VERSION 5.8 ;
BUSBITCHARS "[]" ;
DIVIDERCHAR "/" ;
UNITS
    DATABASE MICRONS 1000 ;
END UNITS

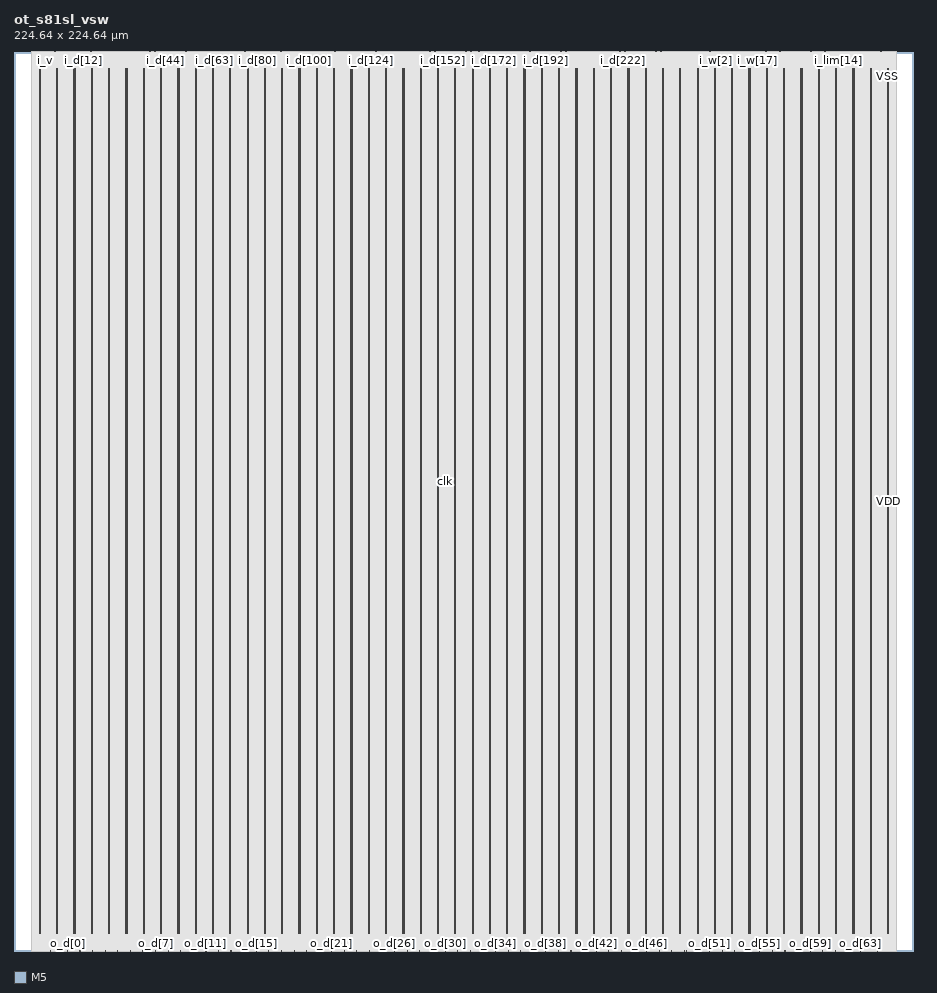
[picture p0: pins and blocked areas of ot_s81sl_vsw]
MACRO ot_s81sl_vsw
  FOREIGN ot_s81sl_vsw 0 0 ;
  CLASS BLOCK ;
  SIZE 224.64 BY 224.64 ;
  PIN clk
    DIRECTION INPUT ;
    USE SIGNAL ;
    PORT
      LAYER M5 ;
        RECT  107.46 116.94 107.508 117.42 ;
    END
  END clk
  PIN i_d[0]
    DIRECTION INPUT ;
    USE SIGNAL ;
    PORT
      LAYER M5 ;
        RECT  9.552 224.556 9.576 224.64 ;
    END
  END i_d[0]
  PIN i_d[100]
    DIRECTION INPUT ;
    USE SIGNAL ;
    PORT
      LAYER M5 ;
        RECT  73.68 224.556 73.704 224.64 ;
    END
  END i_d[100]
  PIN i_d[101]
    DIRECTION INPUT ;
    USE SIGNAL ;
    PORT
      LAYER M5 ;
        RECT  74.304 224.556 74.328 224.64 ;
    END
  END i_d[101]
  PIN i_d[102]
    DIRECTION INPUT ;
    USE SIGNAL ;
    PORT
      LAYER M5 ;
        RECT  74.928 224.556 74.952 224.64 ;
    END
  END i_d[102]
  PIN i_d[103]
    DIRECTION INPUT ;
    USE SIGNAL ;
    PORT
      LAYER M5 ;
        RECT  75.6 224.556 75.624 224.64 ;
    END
  END i_d[103]
  PIN i_d[104]
    DIRECTION INPUT ;
    USE SIGNAL ;
    PORT
      LAYER M5 ;
        RECT  76.224 224.556 76.248 224.64 ;
    END
  END i_d[104]
  PIN i_d[105]
    DIRECTION INPUT ;
    USE SIGNAL ;
    PORT
      LAYER M5 ;
        RECT  76.896 224.556 76.92 224.64 ;
    END
  END i_d[105]
  PIN i_d[106]
    DIRECTION INPUT ;
    USE SIGNAL ;
    PORT
      LAYER M5 ;
        RECT  77.52 224.556 77.544 224.64 ;
    END
  END i_d[106]
  PIN i_d[107]
    DIRECTION INPUT ;
    USE SIGNAL ;
    PORT
      LAYER M5 ;
        RECT  78.144 224.556 78.168 224.64 ;
    END
  END i_d[107]
  PIN i_d[108]
    DIRECTION INPUT ;
    USE SIGNAL ;
    PORT
      LAYER M5 ;
        RECT  78.816 224.556 78.84 224.64 ;
    END
  END i_d[108]
  PIN i_d[109]
    DIRECTION INPUT ;
    USE SIGNAL ;
    PORT
      LAYER M5 ;
        RECT  79.44 224.556 79.464 224.64 ;
    END
  END i_d[109]
  PIN i_d[10]
    DIRECTION INPUT ;
    USE SIGNAL ;
    PORT
      LAYER M5 ;
        RECT  15.984 224.556 16.008 224.64 ;
    END
  END i_d[10]
  PIN i_d[110]
    DIRECTION INPUT ;
    USE SIGNAL ;
    PORT
      LAYER M5 ;
        RECT  80.112 224.556 80.136 224.64 ;
    END
  END i_d[110]
  PIN i_d[111]
    DIRECTION INPUT ;
    USE SIGNAL ;
    PORT
      LAYER M5 ;
        RECT  80.736 224.556 80.76 224.64 ;
    END
  END i_d[111]
  PIN i_d[112]
    DIRECTION INPUT ;
    USE SIGNAL ;
    PORT
      LAYER M5 ;
        RECT  81.408 224.556 81.432 224.64 ;
    END
  END i_d[112]
  PIN i_d[113]
    DIRECTION INPUT ;
    USE SIGNAL ;
    PORT
      LAYER M5 ;
        RECT  82.032 224.556 82.056 224.64 ;
    END
  END i_d[113]
  PIN i_d[114]
    DIRECTION INPUT ;
    USE SIGNAL ;
    PORT
      LAYER M5 ;
        RECT  82.656 224.556 82.68 224.64 ;
    END
  END i_d[114]
  PIN i_d[115]
    DIRECTION INPUT ;
    USE SIGNAL ;
    PORT
      LAYER M5 ;
        RECT  83.28 224.556 83.304 224.64 ;
    END
  END i_d[115]
  PIN i_d[116]
    DIRECTION INPUT ;
    USE SIGNAL ;
    PORT
      LAYER M5 ;
        RECT  83.952 224.556 83.976 224.64 ;
    END
  END i_d[116]
  PIN i_d[117]
    DIRECTION INPUT ;
    USE SIGNAL ;
    PORT
      LAYER M5 ;
        RECT  84.576 224.556 84.6 224.64 ;
    END
  END i_d[117]
  PIN i_d[118]
    DIRECTION INPUT ;
    USE SIGNAL ;
    PORT
      LAYER M5 ;
        RECT  85.2 224.556 85.224 224.64 ;
    END
  END i_d[118]
  PIN i_d[119]
    DIRECTION INPUT ;
    USE SIGNAL ;
    PORT
      LAYER M5 ;
        RECT  85.872 224.556 85.896 224.64 ;
    END
  END i_d[119]
  PIN i_d[11]
    DIRECTION INPUT ;
    USE SIGNAL ;
    PORT
      LAYER M5 ;
        RECT  16.656 224.556 16.68 224.64 ;
    END
  END i_d[11]
  PIN i_d[120]
    DIRECTION INPUT ;
    USE SIGNAL ;
    PORT
      LAYER M5 ;
        RECT  86.496 224.556 86.52 224.64 ;
    END
  END i_d[120]
  PIN i_d[121]
    DIRECTION INPUT ;
    USE SIGNAL ;
    PORT
      LAYER M5 ;
        RECT  87.12 224.556 87.144 224.64 ;
    END
  END i_d[121]
  PIN i_d[122]
    DIRECTION INPUT ;
    USE SIGNAL ;
    PORT
      LAYER M5 ;
        RECT  87.744 224.556 87.768 224.64 ;
    END
  END i_d[122]
  PIN i_d[123]
    DIRECTION INPUT ;
    USE SIGNAL ;
    PORT
      LAYER M5 ;
        RECT  88.416 224.556 88.44 224.64 ;
    END
  END i_d[123]
  PIN i_d[124]
    DIRECTION INPUT ;
    USE SIGNAL ;
    PORT
      LAYER M5 ;
        RECT  89.04 224.556 89.064 224.64 ;
    END
  END i_d[124]
  PIN i_d[125]
    DIRECTION INPUT ;
    USE SIGNAL ;
    PORT
      LAYER M5 ;
        RECT  89.712 224.556 89.736 224.64 ;
    END
  END i_d[125]
  PIN i_d[126]
    DIRECTION INPUT ;
    USE SIGNAL ;
    PORT
      LAYER M5 ;
        RECT  90.336 224.556 90.36 224.64 ;
    END
  END i_d[126]
  PIN i_d[127]
    DIRECTION INPUT ;
    USE SIGNAL ;
    PORT
      LAYER M5 ;
        RECT  91.008 224.556 91.032 224.64 ;
    END
  END i_d[127]
  PIN i_d[128]
    DIRECTION INPUT ;
    USE SIGNAL ;
    PORT
      LAYER M5 ;
        RECT  91.632 224.556 91.656 224.64 ;
    END
  END i_d[128]
  PIN i_d[129]
    DIRECTION INPUT ;
    USE SIGNAL ;
    PORT
      LAYER M5 ;
        RECT  92.256 224.556 92.28 224.64 ;
    END
  END i_d[129]
  PIN i_d[12]
    DIRECTION INPUT ;
    USE SIGNAL ;
    PORT
      LAYER M5 ;
        RECT  17.28 224.556 17.304 224.64 ;
    END
  END i_d[12]
  PIN i_d[130]
    DIRECTION INPUT ;
    USE SIGNAL ;
    PORT
      LAYER M5 ;
        RECT  92.928 224.556 92.952 224.64 ;
    END
  END i_d[130]
  PIN i_d[131]
    DIRECTION INPUT ;
    USE SIGNAL ;
    PORT
      LAYER M5 ;
        RECT  93.552 224.556 93.576 224.64 ;
    END
  END i_d[131]
  PIN i_d[132]
    DIRECTION INPUT ;
    USE SIGNAL ;
    PORT
      LAYER M5 ;
        RECT  94.176 224.556 94.2 224.64 ;
    END
  END i_d[132]
  PIN i_d[133]
    DIRECTION INPUT ;
    USE SIGNAL ;
    PORT
      LAYER M5 ;
        RECT  94.848 224.556 94.872 224.64 ;
    END
  END i_d[133]
  PIN i_d[134]
    DIRECTION INPUT ;
    USE SIGNAL ;
    PORT
      LAYER M5 ;
        RECT  95.472 224.556 95.496 224.64 ;
    END
  END i_d[134]
  PIN i_d[135]
    DIRECTION INPUT ;
    USE SIGNAL ;
    PORT
      LAYER M5 ;
        RECT  96.096 224.556 96.12 224.64 ;
    END
  END i_d[135]
  PIN i_d[136]
    DIRECTION INPUT ;
    USE SIGNAL ;
    PORT
      LAYER M5 ;
        RECT  96.768 224.556 96.792 224.64 ;
    END
  END i_d[136]
  PIN i_d[137]
    DIRECTION INPUT ;
    USE SIGNAL ;
    PORT
      LAYER M5 ;
        RECT  97.392 224.556 97.416 224.64 ;
    END
  END i_d[137]
  PIN i_d[138]
    DIRECTION INPUT ;
    USE SIGNAL ;
    PORT
      LAYER M5 ;
        RECT  98.016 224.556 98.04 224.64 ;
    END
  END i_d[138]
  PIN i_d[139]
    DIRECTION INPUT ;
    USE SIGNAL ;
    PORT
      LAYER M5 ;
        RECT  98.688 224.556 98.712 224.64 ;
    END
  END i_d[139]
  PIN i_d[13]
    DIRECTION INPUT ;
    USE SIGNAL ;
    PORT
      LAYER M5 ;
        RECT  17.904 224.556 17.928 224.64 ;
    END
  END i_d[13]
  PIN i_d[140]
    DIRECTION INPUT ;
    USE SIGNAL ;
    PORT
      LAYER M5 ;
        RECT  99.312 224.556 99.336 224.64 ;
    END
  END i_d[140]
  PIN i_d[141]
    DIRECTION INPUT ;
    USE SIGNAL ;
    PORT
      LAYER M5 ;
        RECT  99.936 224.556 99.96 224.64 ;
    END
  END i_d[141]
  PIN i_d[142]
    DIRECTION INPUT ;
    USE SIGNAL ;
    PORT
      LAYER M5 ;
        RECT  100.56 224.556 100.584 224.64 ;
    END
  END i_d[142]
  PIN i_d[143]
    DIRECTION INPUT ;
    USE SIGNAL ;
    PORT
      LAYER M5 ;
        RECT  101.232 224.556 101.256 224.64 ;
    END
  END i_d[143]
  PIN i_d[144]
    DIRECTION INPUT ;
    USE SIGNAL ;
    PORT
      LAYER M5 ;
        RECT  101.856 224.556 101.88 224.64 ;
    END
  END i_d[144]
  PIN i_d[145]
    DIRECTION INPUT ;
    USE SIGNAL ;
    PORT
      LAYER M5 ;
        RECT  102.528 224.556 102.552 224.64 ;
    END
  END i_d[145]
  PIN i_d[146]
    DIRECTION INPUT ;
    USE SIGNAL ;
    PORT
      LAYER M5 ;
        RECT  103.152 224.556 103.176 224.64 ;
    END
  END i_d[146]
  PIN i_d[147]
    DIRECTION INPUT ;
    USE SIGNAL ;
    PORT
      LAYER M5 ;
        RECT  103.824 224.556 103.848 224.64 ;
    END
  END i_d[147]
  PIN i_d[148]
    DIRECTION INPUT ;
    USE SIGNAL ;
    PORT
      LAYER M5 ;
        RECT  104.448 224.556 104.472 224.64 ;
    END
  END i_d[148]
  PIN i_d[149]
    DIRECTION INPUT ;
    USE SIGNAL ;
    PORT
      LAYER M5 ;
        RECT  105.072 224.556 105.096 224.64 ;
    END
  END i_d[149]
  PIN i_d[14]
    DIRECTION INPUT ;
    USE SIGNAL ;
    PORT
      LAYER M5 ;
        RECT  18.576 224.556 18.6 224.64 ;
    END
  END i_d[14]
  PIN i_d[150]
    DIRECTION INPUT ;
    USE SIGNAL ;
    PORT
      LAYER M5 ;
        RECT  105.744 224.556 105.768 224.64 ;
    END
  END i_d[150]
  PIN i_d[151]
    DIRECTION INPUT ;
    USE SIGNAL ;
    PORT
      LAYER M5 ;
        RECT  106.368 224.556 106.392 224.64 ;
    END
  END i_d[151]
  PIN i_d[152]
    DIRECTION INPUT ;
    USE SIGNAL ;
    PORT
      LAYER M5 ;
        RECT  107.04 224.556 107.064 224.64 ;
    END
  END i_d[152]
  PIN i_d[153]
    DIRECTION INPUT ;
    USE SIGNAL ;
    PORT
      LAYER M5 ;
        RECT  107.664 224.556 107.688 224.64 ;
    END
  END i_d[153]
  PIN i_d[154]
    DIRECTION INPUT ;
    USE SIGNAL ;
    PORT
      LAYER M5 ;
        RECT  108.288 224.556 108.312 224.64 ;
    END
  END i_d[154]
  PIN i_d[155]
    DIRECTION INPUT ;
    USE SIGNAL ;
    PORT
      LAYER M5 ;
        RECT  108.912 224.556 108.936 224.64 ;
    END
  END i_d[155]
  PIN i_d[156]
    DIRECTION INPUT ;
    USE SIGNAL ;
    PORT
      LAYER M5 ;
        RECT  109.584 224.556 109.608 224.64 ;
    END
  END i_d[156]
  PIN i_d[157]
    DIRECTION INPUT ;
    USE SIGNAL ;
    PORT
      LAYER M5 ;
        RECT  110.208 224.556 110.232 224.64 ;
    END
  END i_d[157]
  PIN i_d[158]
    DIRECTION INPUT ;
    USE SIGNAL ;
    PORT
      LAYER M5 ;
        RECT  110.832 224.556 110.856 224.64 ;
    END
  END i_d[158]
  PIN i_d[159]
    DIRECTION INPUT ;
    USE SIGNAL ;
    PORT
      LAYER M5 ;
        RECT  111.504 224.556 111.528 224.64 ;
    END
  END i_d[159]
  PIN i_d[15]
    DIRECTION INPUT ;
    USE SIGNAL ;
    PORT
      LAYER M5 ;
        RECT  19.2 224.556 19.224 224.64 ;
    END
  END i_d[15]
  PIN i_d[160]
    DIRECTION INPUT ;
    USE SIGNAL ;
    PORT
      LAYER M5 ;
        RECT  112.128 224.556 112.152 224.64 ;
    END
  END i_d[160]
  PIN i_d[161]
    DIRECTION INPUT ;
    USE SIGNAL ;
    PORT
      LAYER M5 ;
        RECT  112.8 224.556 112.824 224.64 ;
    END
  END i_d[161]
  PIN i_d[162]
    DIRECTION INPUT ;
    USE SIGNAL ;
    PORT
      LAYER M5 ;
        RECT  113.424 224.556 113.448 224.64 ;
    END
  END i_d[162]
  PIN i_d[163]
    DIRECTION INPUT ;
    USE SIGNAL ;
    PORT
      LAYER M5 ;
        RECT  114.048 224.556 114.072 224.64 ;
    END
  END i_d[163]
  PIN i_d[164]
    DIRECTION INPUT ;
    USE SIGNAL ;
    PORT
      LAYER M5 ;
        RECT  114.672 224.556 114.696 224.64 ;
    END
  END i_d[164]
  PIN i_d[165]
    DIRECTION INPUT ;
    USE SIGNAL ;
    PORT
      LAYER M5 ;
        RECT  115.344 224.556 115.368 224.64 ;
    END
  END i_d[165]
  PIN i_d[166]
    DIRECTION INPUT ;
    USE SIGNAL ;
    PORT
      LAYER M5 ;
        RECT  116.064 224.556 116.088 224.64 ;
    END
  END i_d[166]
  PIN i_d[167]
    DIRECTION INPUT ;
    USE SIGNAL ;
    PORT
      LAYER M5 ;
        RECT  116.64 224.556 116.664 224.64 ;
    END
  END i_d[167]
  PIN i_d[168]
    DIRECTION INPUT ;
    USE SIGNAL ;
    PORT
      LAYER M5 ;
        RECT  117.264 224.556 117.288 224.64 ;
    END
  END i_d[168]
  PIN i_d[169]
    DIRECTION INPUT ;
    USE SIGNAL ;
    PORT
      LAYER M5 ;
        RECT  117.888 224.556 117.912 224.64 ;
    END
  END i_d[169]
  PIN i_d[16]
    DIRECTION INPUT ;
    USE SIGNAL ;
    PORT
      LAYER M5 ;
        RECT  19.824 224.556 19.848 224.64 ;
    END
  END i_d[16]
  PIN i_d[170]
    DIRECTION INPUT ;
    USE SIGNAL ;
    PORT
      LAYER M5 ;
        RECT  118.56 224.556 118.584 224.64 ;
    END
  END i_d[170]
  PIN i_d[171]
    DIRECTION INPUT ;
    USE SIGNAL ;
    PORT
      LAYER M5 ;
        RECT  119.184 224.556 119.208 224.64 ;
    END
  END i_d[171]
  PIN i_d[172]
    DIRECTION INPUT ;
    USE SIGNAL ;
    PORT
      LAYER M5 ;
        RECT  119.856 224.556 119.88 224.64 ;
    END
  END i_d[172]
  PIN i_d[173]
    DIRECTION INPUT ;
    USE SIGNAL ;
    PORT
      LAYER M5 ;
        RECT  120.48 224.556 120.504 224.64 ;
    END
  END i_d[173]
  PIN i_d[174]
    DIRECTION INPUT ;
    USE SIGNAL ;
    PORT
      LAYER M5 ;
        RECT  121.104 224.556 121.128 224.64 ;
    END
  END i_d[174]
  PIN i_d[175]
    DIRECTION INPUT ;
    USE SIGNAL ;
    PORT
      LAYER M5 ;
        RECT  121.728 224.556 121.752 224.64 ;
    END
  END i_d[175]
  PIN i_d[176]
    DIRECTION INPUT ;
    USE SIGNAL ;
    PORT
      LAYER M5 ;
        RECT  122.4 224.556 122.424 224.64 ;
    END
  END i_d[176]
  PIN i_d[177]
    DIRECTION INPUT ;
    USE SIGNAL ;
    PORT
      LAYER M5 ;
        RECT  123.024 224.556 123.048 224.64 ;
    END
  END i_d[177]
  PIN i_d[178]
    DIRECTION INPUT ;
    USE SIGNAL ;
    PORT
      LAYER M5 ;
        RECT  123.648 224.556 123.672 224.64 ;
    END
  END i_d[178]
  PIN i_d[179]
    DIRECTION INPUT ;
    USE SIGNAL ;
    PORT
      LAYER M5 ;
        RECT  124.32 224.556 124.344 224.64 ;
    END
  END i_d[179]
  PIN i_d[17]
    DIRECTION INPUT ;
    USE SIGNAL ;
    PORT
      LAYER M5 ;
        RECT  20.496 224.556 20.52 224.64 ;
    END
  END i_d[17]
  PIN i_d[180]
    DIRECTION INPUT ;
    USE SIGNAL ;
    PORT
      LAYER M5 ;
        RECT  124.944 224.556 124.968 224.64 ;
    END
  END i_d[180]
  PIN i_d[181]
    DIRECTION INPUT ;
    USE SIGNAL ;
    PORT
      LAYER M5 ;
        RECT  125.616 224.556 125.64 224.64 ;
    END
  END i_d[181]
  PIN i_d[182]
    DIRECTION INPUT ;
    USE SIGNAL ;
    PORT
      LAYER M5 ;
        RECT  126.24 224.556 126.264 224.64 ;
    END
  END i_d[182]
  PIN i_d[183]
    DIRECTION INPUT ;
    USE SIGNAL ;
    PORT
      LAYER M5 ;
        RECT  126.864 224.556 126.888 224.64 ;
    END
  END i_d[183]
  PIN i_d[184]
    DIRECTION INPUT ;
    USE SIGNAL ;
    PORT
      LAYER M5 ;
        RECT  127.488 224.556 127.512 224.64 ;
    END
  END i_d[184]
  PIN i_d[185]
    DIRECTION INPUT ;
    USE SIGNAL ;
    PORT
      LAYER M5 ;
        RECT  128.16 224.556 128.184 224.64 ;
    END
  END i_d[185]
  PIN i_d[186]
    DIRECTION INPUT ;
    USE SIGNAL ;
    PORT
      LAYER M5 ;
        RECT  128.784 224.556 128.808 224.64 ;
    END
  END i_d[186]
  PIN i_d[187]
    DIRECTION INPUT ;
    USE SIGNAL ;
    PORT
      LAYER M5 ;
        RECT  129.456 224.556 129.48 224.64 ;
    END
  END i_d[187]
  PIN i_d[188]
    DIRECTION INPUT ;
    USE SIGNAL ;
    PORT
      LAYER M5 ;
        RECT  130.08 224.556 130.104 224.64 ;
    END
  END i_d[188]
  PIN i_d[189]
    DIRECTION INPUT ;
    USE SIGNAL ;
    PORT
      LAYER M5 ;
        RECT  130.704 224.556 130.728 224.64 ;
    END
  END i_d[189]
  PIN i_d[18]
    DIRECTION INPUT ;
    USE SIGNAL ;
    PORT
      LAYER M5 ;
        RECT  21.12 224.556 21.144 224.64 ;
    END
  END i_d[18]
  PIN i_d[190]
    DIRECTION INPUT ;
    USE SIGNAL ;
    PORT
      LAYER M5 ;
        RECT  131.376 224.556 131.4 224.64 ;
    END
  END i_d[190]
  PIN i_d[191]
    DIRECTION INPUT ;
    USE SIGNAL ;
    PORT
      LAYER M5 ;
        RECT  132 224.556 132.024 224.64 ;
    END
  END i_d[191]
  PIN i_d[192]
    DIRECTION INPUT ;
    USE SIGNAL ;
    PORT
      LAYER M5 ;
        RECT  132.672 224.556 132.696 224.64 ;
    END
  END i_d[192]
  PIN i_d[193]
    DIRECTION INPUT ;
    USE SIGNAL ;
    PORT
      LAYER M5 ;
        RECT  133.296 224.556 133.32 224.64 ;
    END
  END i_d[193]
  PIN i_d[194]
    DIRECTION INPUT ;
    USE SIGNAL ;
    PORT
      LAYER M5 ;
        RECT  133.92 224.556 133.944 224.64 ;
    END
  END i_d[194]
  PIN i_d[195]
    DIRECTION INPUT ;
    USE SIGNAL ;
    PORT
      LAYER M5 ;
        RECT  134.592 224.556 134.616 224.64 ;
    END
  END i_d[195]
  PIN i_d[196]
    DIRECTION INPUT ;
    USE SIGNAL ;
    PORT
      LAYER M5 ;
        RECT  135.216 224.556 135.24 224.64 ;
    END
  END i_d[196]
  PIN i_d[197]
    DIRECTION INPUT ;
    USE SIGNAL ;
    PORT
      LAYER M5 ;
        RECT  135.84 224.556 135.864 224.64 ;
    END
  END i_d[197]
  PIN i_d[198]
    DIRECTION INPUT ;
    USE SIGNAL ;
    PORT
      LAYER M5 ;
        RECT  136.512 224.556 136.536 224.64 ;
    END
  END i_d[198]
  PIN i_d[199]
    DIRECTION INPUT ;
    USE SIGNAL ;
    PORT
      LAYER M5 ;
        RECT  137.136 224.556 137.16 224.64 ;
    END
  END i_d[199]
  PIN i_d[19]
    DIRECTION INPUT ;
    USE SIGNAL ;
    PORT
      LAYER M5 ;
        RECT  21.744 224.556 21.768 224.64 ;
    END
  END i_d[19]
  PIN i_d[1]
    DIRECTION INPUT ;
    USE SIGNAL ;
    PORT
      LAYER M5 ;
        RECT  10.224 224.556 10.248 224.64 ;
    END
  END i_d[1]
  PIN i_d[200]
    DIRECTION INPUT ;
    USE SIGNAL ;
    PORT
      LAYER M5 ;
        RECT  137.76 224.556 137.784 224.64 ;
    END
  END i_d[200]
  PIN i_d[201]
    DIRECTION INPUT ;
    USE SIGNAL ;
    PORT
      LAYER M5 ;
        RECT  138.432 224.556 138.456 224.64 ;
    END
  END i_d[201]
  PIN i_d[202]
    DIRECTION INPUT ;
    USE SIGNAL ;
    PORT
      LAYER M5 ;
        RECT  139.056 224.556 139.08 224.64 ;
    END
  END i_d[202]
  PIN i_d[203]
    DIRECTION INPUT ;
    USE SIGNAL ;
    PORT
      LAYER M5 ;
        RECT  139.68 224.556 139.704 224.64 ;
    END
  END i_d[203]
  PIN i_d[204]
    DIRECTION INPUT ;
    USE SIGNAL ;
    PORT
      LAYER M5 ;
        RECT  140.304 224.556 140.328 224.64 ;
    END
  END i_d[204]
  PIN i_d[205]
    DIRECTION INPUT ;
    USE SIGNAL ;
    PORT
      LAYER M5 ;
        RECT  140.976 224.556 141 224.64 ;
    END
  END i_d[205]
  PIN i_d[206]
    DIRECTION INPUT ;
    USE SIGNAL ;
    PORT
      LAYER M5 ;
        RECT  141.6 224.556 141.624 224.64 ;
    END
  END i_d[206]
  PIN i_d[207]
    DIRECTION INPUT ;
    USE SIGNAL ;
    PORT
      LAYER M5 ;
        RECT  142.272 224.556 142.296 224.64 ;
    END
  END i_d[207]
  PIN i_d[208]
    DIRECTION INPUT ;
    USE SIGNAL ;
    PORT
      LAYER M5 ;
        RECT  142.896 224.556 142.92 224.64 ;
    END
  END i_d[208]
  PIN i_d[209]
    DIRECTION INPUT ;
    USE SIGNAL ;
    PORT
      LAYER M5 ;
        RECT  143.52 224.556 143.544 224.64 ;
    END
  END i_d[209]
  PIN i_d[20]
    DIRECTION INPUT ;
    USE SIGNAL ;
    PORT
      LAYER M5 ;
        RECT  22.368 224.556 22.392 224.64 ;
    END
  END i_d[20]
  PIN i_d[210]
    DIRECTION INPUT ;
    USE SIGNAL ;
    PORT
      LAYER M5 ;
        RECT  144.192 224.556 144.216 224.64 ;
    END
  END i_d[210]
  PIN i_d[211]
    DIRECTION INPUT ;
    USE SIGNAL ;
    PORT
      LAYER M5 ;
        RECT  144.816 224.556 144.84 224.64 ;
    END
  END i_d[211]
  PIN i_d[212]
    DIRECTION INPUT ;
    USE SIGNAL ;
    PORT
      LAYER M5 ;
        RECT  145.488 224.556 145.512 224.64 ;
    END
  END i_d[212]
  PIN i_d[213]
    DIRECTION INPUT ;
    USE SIGNAL ;
    PORT
      LAYER M5 ;
        RECT  146.112 224.556 146.136 224.64 ;
    END
  END i_d[213]
  PIN i_d[214]
    DIRECTION INPUT ;
    USE SIGNAL ;
    PORT
      LAYER M5 ;
        RECT  146.736 224.556 146.76 224.64 ;
    END
  END i_d[214]
  PIN i_d[215]
    DIRECTION INPUT ;
    USE SIGNAL ;
    PORT
      LAYER M5 ;
        RECT  147.408 224.556 147.432 224.64 ;
    END
  END i_d[215]
  PIN i_d[216]
    DIRECTION INPUT ;
    USE SIGNAL ;
    PORT
      LAYER M5 ;
        RECT  148.032 224.556 148.056 224.64 ;
    END
  END i_d[216]
  PIN i_d[217]
    DIRECTION INPUT ;
    USE SIGNAL ;
    PORT
      LAYER M5 ;
        RECT  148.656 224.556 148.68 224.64 ;
    END
  END i_d[217]
  PIN i_d[218]
    DIRECTION INPUT ;
    USE SIGNAL ;
    PORT
      LAYER M5 ;
        RECT  149.328 224.556 149.352 224.64 ;
    END
  END i_d[218]
  PIN i_d[219]
    DIRECTION INPUT ;
    USE SIGNAL ;
    PORT
      LAYER M5 ;
        RECT  149.952 224.556 149.976 224.64 ;
    END
  END i_d[219]
  PIN i_d[21]
    DIRECTION INPUT ;
    USE SIGNAL ;
    PORT
      LAYER M5 ;
        RECT  23.04 224.556 23.064 224.64 ;
    END
  END i_d[21]
  PIN i_d[220]
    DIRECTION INPUT ;
    USE SIGNAL ;
    PORT
      LAYER M5 ;
        RECT  150.576 224.556 150.6 224.64 ;
    END
  END i_d[220]
  PIN i_d[221]
    DIRECTION INPUT ;
    USE SIGNAL ;
    PORT
      LAYER M5 ;
        RECT  151.248 224.556 151.272 224.64 ;
    END
  END i_d[221]
  PIN i_d[222]
    DIRECTION INPUT ;
    USE SIGNAL ;
    PORT
      LAYER M5 ;
        RECT  151.872 224.556 151.896 224.64 ;
    END
  END i_d[222]
  PIN i_d[223]
    DIRECTION INPUT ;
    USE SIGNAL ;
    PORT
      LAYER M5 ;
        RECT  152.496 224.556 152.52 224.64 ;
    END
  END i_d[223]
  PIN i_d[224]
    DIRECTION INPUT ;
    USE SIGNAL ;
    PORT
      LAYER M5 ;
        RECT  153.12 224.556 153.144 224.64 ;
    END
  END i_d[224]
  PIN i_d[225]
    DIRECTION INPUT ;
    USE SIGNAL ;
    PORT
      LAYER M5 ;
        RECT  153.792 224.556 153.816 224.64 ;
    END
  END i_d[225]
  PIN i_d[226]
    DIRECTION INPUT ;
    USE SIGNAL ;
    PORT
      LAYER M5 ;
        RECT  154.416 224.556 154.44 224.64 ;
    END
  END i_d[226]
  PIN i_d[227]
    DIRECTION INPUT ;
    USE SIGNAL ;
    PORT
      LAYER M5 ;
        RECT  155.088 224.556 155.112 224.64 ;
    END
  END i_d[227]
  PIN i_d[228]
    DIRECTION INPUT ;
    USE SIGNAL ;
    PORT
      LAYER M5 ;
        RECT  155.712 224.556 155.736 224.64 ;
    END
  END i_d[228]
  PIN i_d[229]
    DIRECTION INPUT ;
    USE SIGNAL ;
    PORT
      LAYER M5 ;
        RECT  156.384 224.556 156.408 224.64 ;
    END
  END i_d[229]
  PIN i_d[22]
    DIRECTION INPUT ;
    USE SIGNAL ;
    PORT
      LAYER M5 ;
        RECT  23.664 224.556 23.688 224.64 ;
    END
  END i_d[22]
  PIN i_d[230]
    DIRECTION INPUT ;
    USE SIGNAL ;
    PORT
      LAYER M5 ;
        RECT  157.008 224.556 157.032 224.64 ;
    END
  END i_d[230]
  PIN i_d[231]
    DIRECTION INPUT ;
    USE SIGNAL ;
    PORT
      LAYER M5 ;
        RECT  157.632 224.556 157.656 224.64 ;
    END
  END i_d[231]
  PIN i_d[232]
    DIRECTION INPUT ;
    USE SIGNAL ;
    PORT
      LAYER M5 ;
        RECT  158.304 224.556 158.328 224.64 ;
    END
  END i_d[232]
  PIN i_d[233]
    DIRECTION INPUT ;
    USE SIGNAL ;
    PORT
      LAYER M5 ;
        RECT  158.928 224.556 158.952 224.64 ;
    END
  END i_d[233]
  PIN i_d[234]
    DIRECTION INPUT ;
    USE SIGNAL ;
    PORT
      LAYER M5 ;
        RECT  159.552 224.556 159.576 224.64 ;
    END
  END i_d[234]
  PIN i_d[235]
    DIRECTION INPUT ;
    USE SIGNAL ;
    PORT
      LAYER M5 ;
        RECT  160.224 224.556 160.248 224.64 ;
    END
  END i_d[235]
  PIN i_d[236]
    DIRECTION INPUT ;
    USE SIGNAL ;
    PORT
      LAYER M5 ;
        RECT  160.848 224.556 160.872 224.64 ;
    END
  END i_d[236]
  PIN i_d[237]
    DIRECTION INPUT ;
    USE SIGNAL ;
    PORT
      LAYER M5 ;
        RECT  161.472 224.556 161.496 224.64 ;
    END
  END i_d[237]
  PIN i_d[238]
    DIRECTION INPUT ;
    USE SIGNAL ;
    PORT
      LAYER M5 ;
        RECT  162.144 224.556 162.168 224.64 ;
    END
  END i_d[238]
  PIN i_d[239]
    DIRECTION INPUT ;
    USE SIGNAL ;
    PORT
      LAYER M5 ;
        RECT  162.768 224.556 162.792 224.64 ;
    END
  END i_d[239]
  PIN i_d[23]
    DIRECTION INPUT ;
    USE SIGNAL ;
    PORT
      LAYER M5 ;
        RECT  24.336 224.556 24.36 224.64 ;
    END
  END i_d[23]
  PIN i_d[240]
    DIRECTION INPUT ;
    USE SIGNAL ;
    PORT
      LAYER M5 ;
        RECT  163.392 224.556 163.416 224.64 ;
    END
  END i_d[240]
  PIN i_d[241]
    DIRECTION INPUT ;
    USE SIGNAL ;
    PORT
      LAYER M5 ;
        RECT  164.064 224.556 164.088 224.64 ;
    END
  END i_d[241]
  PIN i_d[242]
    DIRECTION INPUT ;
    USE SIGNAL ;
    PORT
      LAYER M5 ;
        RECT  164.688 224.556 164.712 224.64 ;
    END
  END i_d[242]
  PIN i_d[243]
    DIRECTION INPUT ;
    USE SIGNAL ;
    PORT
      LAYER M5 ;
        RECT  165.312 224.556 165.336 224.64 ;
    END
  END i_d[243]
  PIN i_d[244]
    DIRECTION INPUT ;
    USE SIGNAL ;
    PORT
      LAYER M5 ;
        RECT  165.984 224.556 166.008 224.64 ;
    END
  END i_d[244]
  PIN i_d[245]
    DIRECTION INPUT ;
    USE SIGNAL ;
    PORT
      LAYER M5 ;
        RECT  166.608 224.556 166.632 224.64 ;
    END
  END i_d[245]
  PIN i_d[246]
    DIRECTION INPUT ;
    USE SIGNAL ;
    PORT
      LAYER M5 ;
        RECT  167.232 224.556 167.256 224.64 ;
    END
  END i_d[246]
  PIN i_d[247]
    DIRECTION INPUT ;
    USE SIGNAL ;
    PORT
      LAYER M5 ;
        RECT  167.904 224.556 167.928 224.64 ;
    END
  END i_d[247]
  PIN i_d[248]
    DIRECTION INPUT ;
    USE SIGNAL ;
    PORT
      LAYER M5 ;
        RECT  168.528 224.556 168.552 224.64 ;
    END
  END i_d[248]
  PIN i_d[249]
    DIRECTION INPUT ;
    USE SIGNAL ;
    PORT
      LAYER M5 ;
        RECT  169.2 224.556 169.224 224.64 ;
    END
  END i_d[249]
  PIN i_d[24]
    DIRECTION INPUT ;
    USE SIGNAL ;
    PORT
      LAYER M5 ;
        RECT  24.96 224.556 24.984 224.64 ;
    END
  END i_d[24]
  PIN i_d[250]
    DIRECTION INPUT ;
    USE SIGNAL ;
    PORT
      LAYER M5 ;
        RECT  169.824 224.556 169.848 224.64 ;
    END
  END i_d[250]
  PIN i_d[251]
    DIRECTION INPUT ;
    USE SIGNAL ;
    PORT
      LAYER M5 ;
        RECT  170.448 224.556 170.472 224.64 ;
    END
  END i_d[251]
  PIN i_d[252]
    DIRECTION INPUT ;
    USE SIGNAL ;
    PORT
      LAYER M5 ;
        RECT  171.12 224.556 171.144 224.64 ;
    END
  END i_d[252]
  PIN i_d[253]
    DIRECTION INPUT ;
    USE SIGNAL ;
    PORT
      LAYER M5 ;
        RECT  171.744 224.556 171.768 224.64 ;
    END
  END i_d[253]
  PIN i_d[254]
    DIRECTION INPUT ;
    USE SIGNAL ;
    PORT
      LAYER M5 ;
        RECT  172.416 224.556 172.44 224.64 ;
    END
  END i_d[254]
  PIN i_d[255]
    DIRECTION INPUT ;
    USE SIGNAL ;
    PORT
      LAYER M5 ;
        RECT  173.04 224.556 173.064 224.64 ;
    END
  END i_d[255]
  PIN i_d[25]
    DIRECTION INPUT ;
    USE SIGNAL ;
    PORT
      LAYER M5 ;
        RECT  25.584 224.556 25.608 224.64 ;
    END
  END i_d[25]
  PIN i_d[26]
    DIRECTION INPUT ;
    USE SIGNAL ;
    PORT
      LAYER M5 ;
        RECT  26.256 224.556 26.28 224.64 ;
    END
  END i_d[26]
  PIN i_d[27]
    DIRECTION INPUT ;
    USE SIGNAL ;
    PORT
      LAYER M5 ;
        RECT  26.88 224.556 26.904 224.64 ;
    END
  END i_d[27]
  PIN i_d[28]
    DIRECTION INPUT ;
    USE SIGNAL ;
    PORT
      LAYER M5 ;
        RECT  27.552 224.556 27.576 224.64 ;
    END
  END i_d[28]
  PIN i_d[29]
    DIRECTION INPUT ;
    USE SIGNAL ;
    PORT
      LAYER M5 ;
        RECT  28.176 224.556 28.2 224.64 ;
    END
  END i_d[29]
  PIN i_d[2]
    DIRECTION INPUT ;
    USE SIGNAL ;
    PORT
      LAYER M5 ;
        RECT  10.848 224.556 10.872 224.64 ;
    END
  END i_d[2]
  PIN i_d[30]
    DIRECTION INPUT ;
    USE SIGNAL ;
    PORT
      LAYER M5 ;
        RECT  28.8 224.556 28.824 224.64 ;
    END
  END i_d[30]
  PIN i_d[31]
    DIRECTION INPUT ;
    USE SIGNAL ;
    PORT
      LAYER M5 ;
        RECT  29.472 224.556 29.496 224.64 ;
    END
  END i_d[31]
  PIN i_d[32]
    DIRECTION INPUT ;
    USE SIGNAL ;
    PORT
      LAYER M5 ;
        RECT  30.096 224.556 30.12 224.64 ;
    END
  END i_d[32]
  PIN i_d[33]
    DIRECTION INPUT ;
    USE SIGNAL ;
    PORT
      LAYER M5 ;
        RECT  30.72 224.556 30.744 224.64 ;
    END
  END i_d[33]
  PIN i_d[34]
    DIRECTION INPUT ;
    USE SIGNAL ;
    PORT
      LAYER M5 ;
        RECT  31.392 224.556 31.416 224.64 ;
    END
  END i_d[34]
  PIN i_d[35]
    DIRECTION INPUT ;
    USE SIGNAL ;
    PORT
      LAYER M5 ;
        RECT  32.016 224.556 32.04 224.64 ;
    END
  END i_d[35]
  PIN i_d[36]
    DIRECTION INPUT ;
    USE SIGNAL ;
    PORT
      LAYER M5 ;
        RECT  32.64 224.556 32.664 224.64 ;
    END
  END i_d[36]
  PIN i_d[37]
    DIRECTION INPUT ;
    USE SIGNAL ;
    PORT
      LAYER M5 ;
        RECT  33.312 224.556 33.336 224.64 ;
    END
  END i_d[37]
  PIN i_d[38]
    DIRECTION INPUT ;
    USE SIGNAL ;
    PORT
      LAYER M5 ;
        RECT  33.936 224.556 33.96 224.64 ;
    END
  END i_d[38]
  PIN i_d[39]
    DIRECTION INPUT ;
    USE SIGNAL ;
    PORT
      LAYER M5 ;
        RECT  34.56 224.556 34.584 224.64 ;
    END
  END i_d[39]
  PIN i_d[3]
    DIRECTION INPUT ;
    USE SIGNAL ;
    PORT
      LAYER M5 ;
        RECT  11.52 224.556 11.544 224.64 ;
    END
  END i_d[3]
  PIN i_d[40]
    DIRECTION INPUT ;
    USE SIGNAL ;
    PORT
      LAYER M5 ;
        RECT  35.184 224.556 35.208 224.64 ;
    END
  END i_d[40]
  PIN i_d[41]
    DIRECTION INPUT ;
    USE SIGNAL ;
    PORT
      LAYER M5 ;
        RECT  35.856 224.556 35.88 224.64 ;
    END
  END i_d[41]
  PIN i_d[42]
    DIRECTION INPUT ;
    USE SIGNAL ;
    PORT
      LAYER M5 ;
        RECT  36.48 224.556 36.504 224.64 ;
    END
  END i_d[42]
  PIN i_d[43]
    DIRECTION INPUT ;
    USE SIGNAL ;
    PORT
      LAYER M5 ;
        RECT  37.152 224.556 37.176 224.64 ;
    END
  END i_d[43]
  PIN i_d[44]
    DIRECTION INPUT ;
    USE SIGNAL ;
    PORT
      LAYER M5 ;
        RECT  37.776 224.556 37.8 224.64 ;
    END
  END i_d[44]
  PIN i_d[45]
    DIRECTION INPUT ;
    USE SIGNAL ;
    PORT
      LAYER M5 ;
        RECT  38.448 224.556 38.472 224.64 ;
    END
  END i_d[45]
  PIN i_d[46]
    DIRECTION INPUT ;
    USE SIGNAL ;
    PORT
      LAYER M5 ;
        RECT  39.072 224.556 39.096 224.64 ;
    END
  END i_d[46]
  PIN i_d[47]
    DIRECTION INPUT ;
    USE SIGNAL ;
    PORT
      LAYER M5 ;
        RECT  39.696 224.556 39.72 224.64 ;
    END
  END i_d[47]
  PIN i_d[48]
    DIRECTION INPUT ;
    USE SIGNAL ;
    PORT
      LAYER M5 ;
        RECT  40.368 224.556 40.392 224.64 ;
    END
  END i_d[48]
  PIN i_d[49]
    DIRECTION INPUT ;
    USE SIGNAL ;
    PORT
      LAYER M5 ;
        RECT  40.992 224.556 41.016 224.64 ;
    END
  END i_d[49]
  PIN i_d[4]
    DIRECTION INPUT ;
    USE SIGNAL ;
    PORT
      LAYER M5 ;
        RECT  12.144 224.556 12.168 224.64 ;
    END
  END i_d[4]
  PIN i_d[50]
    DIRECTION INPUT ;
    USE SIGNAL ;
    PORT
      LAYER M5 ;
        RECT  41.616 224.556 41.64 224.64 ;
    END
  END i_d[50]
  PIN i_d[51]
    DIRECTION INPUT ;
    USE SIGNAL ;
    PORT
      LAYER M5 ;
        RECT  42.288 224.556 42.312 224.64 ;
    END
  END i_d[51]
  PIN i_d[52]
    DIRECTION INPUT ;
    USE SIGNAL ;
    PORT
      LAYER M5 ;
        RECT  42.912 224.556 42.936 224.64 ;
    END
  END i_d[52]
  PIN i_d[53]
    DIRECTION INPUT ;
    USE SIGNAL ;
    PORT
      LAYER M5 ;
        RECT  43.536 224.556 43.56 224.64 ;
    END
  END i_d[53]
  PIN i_d[54]
    DIRECTION INPUT ;
    USE SIGNAL ;
    PORT
      LAYER M5 ;
        RECT  44.208 224.556 44.232 224.64 ;
    END
  END i_d[54]
  PIN i_d[55]
    DIRECTION INPUT ;
    USE SIGNAL ;
    PORT
      LAYER M5 ;
        RECT  44.832 224.556 44.856 224.64 ;
    END
  END i_d[55]
  PIN i_d[56]
    DIRECTION INPUT ;
    USE SIGNAL ;
    PORT
      LAYER M5 ;
        RECT  45.456 224.556 45.48 224.64 ;
    END
  END i_d[56]
  PIN i_d[57]
    DIRECTION INPUT ;
    USE SIGNAL ;
    PORT
      LAYER M5 ;
        RECT  46.128 224.556 46.152 224.64 ;
    END
  END i_d[57]
  PIN i_d[58]
    DIRECTION INPUT ;
    USE SIGNAL ;
    PORT
      LAYER M5 ;
        RECT  46.752 224.556 46.776 224.64 ;
    END
  END i_d[58]
  PIN i_d[59]
    DIRECTION INPUT ;
    USE SIGNAL ;
    PORT
      LAYER M5 ;
        RECT  47.376 224.556 47.4 224.64 ;
    END
  END i_d[59]
  PIN i_d[5]
    DIRECTION INPUT ;
    USE SIGNAL ;
    PORT
      LAYER M5 ;
        RECT  12.768 224.556 12.792 224.64 ;
    END
  END i_d[5]
  PIN i_d[60]
    DIRECTION INPUT ;
    USE SIGNAL ;
    PORT
      LAYER M5 ;
        RECT  48.048 224.556 48.072 224.64 ;
    END
  END i_d[60]
  PIN i_d[61]
    DIRECTION INPUT ;
    USE SIGNAL ;
    PORT
      LAYER M5 ;
        RECT  48.672 224.556 48.696 224.64 ;
    END
  END i_d[61]
  PIN i_d[62]
    DIRECTION INPUT ;
    USE SIGNAL ;
    PORT
      LAYER M5 ;
        RECT  49.296 224.556 49.32 224.64 ;
    END
  END i_d[62]
  PIN i_d[63]
    DIRECTION INPUT ;
    USE SIGNAL ;
    PORT
      LAYER M5 ;
        RECT  49.968 224.556 49.992 224.64 ;
    END
  END i_d[63]
  PIN i_d[64]
    DIRECTION INPUT ;
    USE SIGNAL ;
    PORT
      LAYER M5 ;
        RECT  50.592 224.556 50.616 224.64 ;
    END
  END i_d[64]
  PIN i_d[65]
    DIRECTION INPUT ;
    USE SIGNAL ;
    PORT
      LAYER M5 ;
        RECT  51.264 224.556 51.288 224.64 ;
    END
  END i_d[65]
  PIN i_d[66]
    DIRECTION INPUT ;
    USE SIGNAL ;
    PORT
      LAYER M5 ;
        RECT  51.888 224.556 51.912 224.64 ;
    END
  END i_d[66]
  PIN i_d[67]
    DIRECTION INPUT ;
    USE SIGNAL ;
    PORT
      LAYER M5 ;
        RECT  52.512 224.556 52.536 224.64 ;
    END
  END i_d[67]
  PIN i_d[68]
    DIRECTION INPUT ;
    USE SIGNAL ;
    PORT
      LAYER M5 ;
        RECT  53.184 224.556 53.208 224.64 ;
    END
  END i_d[68]
  PIN i_d[69]
    DIRECTION INPUT ;
    USE SIGNAL ;
    PORT
      LAYER M5 ;
        RECT  53.808 224.556 53.832 224.64 ;
    END
  END i_d[69]
  PIN i_d[6]
    DIRECTION INPUT ;
    USE SIGNAL ;
    PORT
      LAYER M5 ;
        RECT  13.44 224.556 13.464 224.64 ;
    END
  END i_d[6]
  PIN i_d[70]
    DIRECTION INPUT ;
    USE SIGNAL ;
    PORT
      LAYER M5 ;
        RECT  54.48 224.556 54.504 224.64 ;
    END
  END i_d[70]
  PIN i_d[71]
    DIRECTION INPUT ;
    USE SIGNAL ;
    PORT
      LAYER M5 ;
        RECT  55.104 224.556 55.128 224.64 ;
    END
  END i_d[71]
  PIN i_d[72]
    DIRECTION INPUT ;
    USE SIGNAL ;
    PORT
      LAYER M5 ;
        RECT  55.728 224.556 55.752 224.64 ;
    END
  END i_d[72]
  PIN i_d[73]
    DIRECTION INPUT ;
    USE SIGNAL ;
    PORT
      LAYER M5 ;
        RECT  56.352 224.556 56.376 224.64 ;
    END
  END i_d[73]
  PIN i_d[74]
    DIRECTION INPUT ;
    USE SIGNAL ;
    PORT
      LAYER M5 ;
        RECT  57.024 224.556 57.048 224.64 ;
    END
  END i_d[74]
  PIN i_d[75]
    DIRECTION INPUT ;
    USE SIGNAL ;
    PORT
      LAYER M5 ;
        RECT  57.648 224.556 57.672 224.64 ;
    END
  END i_d[75]
  PIN i_d[76]
    DIRECTION INPUT ;
    USE SIGNAL ;
    PORT
      LAYER M5 ;
        RECT  58.272 224.556 58.296 224.64 ;
    END
  END i_d[76]
  PIN i_d[77]
    DIRECTION INPUT ;
    USE SIGNAL ;
    PORT
      LAYER M5 ;
        RECT  58.944 224.556 58.968 224.64 ;
    END
  END i_d[77]
  PIN i_d[78]
    DIRECTION INPUT ;
    USE SIGNAL ;
    PORT
      LAYER M5 ;
        RECT  59.568 224.556 59.592 224.64 ;
    END
  END i_d[78]
  PIN i_d[79]
    DIRECTION INPUT ;
    USE SIGNAL ;
    PORT
      LAYER M5 ;
        RECT  60.24 224.556 60.264 224.64 ;
    END
  END i_d[79]
  PIN i_d[7]
    DIRECTION INPUT ;
    USE SIGNAL ;
    PORT
      LAYER M5 ;
        RECT  14.064 224.556 14.088 224.64 ;
    END
  END i_d[7]
  PIN i_d[80]
    DIRECTION INPUT ;
    USE SIGNAL ;
    PORT
      LAYER M5 ;
        RECT  60.864 224.556 60.888 224.64 ;
    END
  END i_d[80]
  PIN i_d[81]
    DIRECTION INPUT ;
    USE SIGNAL ;
    PORT
      LAYER M5 ;
        RECT  61.488 224.556 61.512 224.64 ;
    END
  END i_d[81]
  PIN i_d[82]
    DIRECTION INPUT ;
    USE SIGNAL ;
    PORT
      LAYER M5 ;
        RECT  62.112 224.556 62.136 224.64 ;
    END
  END i_d[82]
  PIN i_d[83]
    DIRECTION INPUT ;
    USE SIGNAL ;
    PORT
      LAYER M5 ;
        RECT  62.784 224.556 62.808 224.64 ;
    END
  END i_d[83]
  PIN i_d[84]
    DIRECTION INPUT ;
    USE SIGNAL ;
    PORT
      LAYER M5 ;
        RECT  63.408 224.556 63.432 224.64 ;
    END
  END i_d[84]
  PIN i_d[85]
    DIRECTION INPUT ;
    USE SIGNAL ;
    PORT
      LAYER M5 ;
        RECT  64.08 224.556 64.104 224.64 ;
    END
  END i_d[85]
  PIN i_d[86]
    DIRECTION INPUT ;
    USE SIGNAL ;
    PORT
      LAYER M5 ;
        RECT  64.704 224.556 64.728 224.64 ;
    END
  END i_d[86]
  PIN i_d[87]
    DIRECTION INPUT ;
    USE SIGNAL ;
    PORT
      LAYER M5 ;
        RECT  65.328 224.556 65.352 224.64 ;
    END
  END i_d[87]
  PIN i_d[88]
    DIRECTION INPUT ;
    USE SIGNAL ;
    PORT
      LAYER M5 ;
        RECT  66 224.556 66.024 224.64 ;
    END
  END i_d[88]
  PIN i_d[89]
    DIRECTION INPUT ;
    USE SIGNAL ;
    PORT
      LAYER M5 ;
        RECT  66.624 224.556 66.648 224.64 ;
    END
  END i_d[89]
  PIN i_d[8]
    DIRECTION INPUT ;
    USE SIGNAL ;
    PORT
      LAYER M5 ;
        RECT  14.736 224.556 14.76 224.64 ;
    END
  END i_d[8]
  PIN i_d[90]
    DIRECTION INPUT ;
    USE SIGNAL ;
    PORT
      LAYER M5 ;
        RECT  67.296 224.556 67.32 224.64 ;
    END
  END i_d[90]
  PIN i_d[91]
    DIRECTION INPUT ;
    USE SIGNAL ;
    PORT
      LAYER M5 ;
        RECT  67.92 224.556 67.944 224.64 ;
    END
  END i_d[91]
  PIN i_d[92]
    DIRECTION INPUT ;
    USE SIGNAL ;
    PORT
      LAYER M5 ;
        RECT  68.544 224.556 68.568 224.64 ;
    END
  END i_d[92]
  PIN i_d[93]
    DIRECTION INPUT ;
    USE SIGNAL ;
    PORT
      LAYER M5 ;
        RECT  69.168 224.556 69.192 224.64 ;
    END
  END i_d[93]
  PIN i_d[94]
    DIRECTION INPUT ;
    USE SIGNAL ;
    PORT
      LAYER M5 ;
        RECT  69.84 224.556 69.864 224.64 ;
    END
  END i_d[94]
  PIN i_d[95]
    DIRECTION INPUT ;
    USE SIGNAL ;
    PORT
      LAYER M5 ;
        RECT  70.464 224.556 70.488 224.64 ;
    END
  END i_d[95]
  PIN i_d[96]
    DIRECTION INPUT ;
    USE SIGNAL ;
    PORT
      LAYER M5 ;
        RECT  71.088 224.556 71.112 224.64 ;
    END
  END i_d[96]
  PIN i_d[97]
    DIRECTION INPUT ;
    USE SIGNAL ;
    PORT
      LAYER M5 ;
        RECT  71.76 224.556 71.784 224.64 ;
    END
  END i_d[97]
  PIN i_d[98]
    DIRECTION INPUT ;
    USE SIGNAL ;
    PORT
      LAYER M5 ;
        RECT  72.384 224.556 72.408 224.64 ;
    END
  END i_d[98]
  PIN i_d[99]
    DIRECTION INPUT ;
    USE SIGNAL ;
    PORT
      LAYER M5 ;
        RECT  73.056 224.556 73.08 224.64 ;
    END
  END i_d[99]
  PIN i_d[9]
    DIRECTION INPUT ;
    USE SIGNAL ;
    PORT
      LAYER M5 ;
        RECT  15.36 224.556 15.384 224.64 ;
    END
  END i_d[9]
  PIN i_lim[0]
    DIRECTION INPUT ;
    USE SIGNAL ;
    PORT
      LAYER M5 ;
        RECT  196.08 224.556 196.104 224.64 ;
    END
  END i_lim[0]
  PIN i_lim[10]
    DIRECTION INPUT ;
    USE SIGNAL ;
    PORT
      LAYER M5 ;
        RECT  203.088 224.556 203.112 224.64 ;
    END
  END i_lim[10]
  PIN i_lim[11]
    DIRECTION INPUT ;
    USE SIGNAL ;
    PORT
      LAYER M5 ;
        RECT  203.808 224.556 203.832 224.64 ;
    END
  END i_lim[11]
  PIN i_lim[12]
    DIRECTION INPUT ;
    USE SIGNAL ;
    PORT
      LAYER M5 ;
        RECT  204.528 224.556 204.552 224.64 ;
    END
  END i_lim[12]
  PIN i_lim[13]
    DIRECTION INPUT ;
    USE SIGNAL ;
    PORT
      LAYER M5 ;
        RECT  205.2 224.556 205.224 224.64 ;
    END
  END i_lim[13]
  PIN i_lim[14]
    DIRECTION INPUT ;
    USE SIGNAL ;
    PORT
      LAYER M5 ;
        RECT  205.872 224.556 205.896 224.64 ;
    END
  END i_lim[14]
  PIN i_lim[15]
    DIRECTION INPUT ;
    USE SIGNAL ;
    PORT
      LAYER M5 ;
        RECT  206.592 224.556 206.616 224.64 ;
    END
  END i_lim[15]
  PIN i_lim[16]
    DIRECTION INPUT ;
    USE SIGNAL ;
    PORT
      LAYER M5 ;
        RECT  207.264 224.556 207.288 224.64 ;
    END
  END i_lim[16]
  PIN i_lim[17]
    DIRECTION INPUT ;
    USE SIGNAL ;
    PORT
      LAYER M5 ;
        RECT  207.984 224.556 208.008 224.64 ;
    END
  END i_lim[17]
  PIN i_lim[18]
    DIRECTION INPUT ;
    USE SIGNAL ;
    PORT
      LAYER M5 ;
        RECT  208.704 224.556 208.728 224.64 ;
    END
  END i_lim[18]
  PIN i_lim[19]
    DIRECTION INPUT ;
    USE SIGNAL ;
    PORT
      LAYER M5 ;
        RECT  209.376 224.556 209.4 224.64 ;
    END
  END i_lim[19]
  PIN i_lim[1]
    DIRECTION INPUT ;
    USE SIGNAL ;
    PORT
      LAYER M5 ;
        RECT  196.8 224.556 196.824 224.64 ;
    END
  END i_lim[1]
  PIN i_lim[20]
    DIRECTION INPUT ;
    USE SIGNAL ;
    PORT
      LAYER M5 ;
        RECT  210.096 224.556 210.12 224.64 ;
    END
  END i_lim[20]
  PIN i_lim[21]
    DIRECTION INPUT ;
    USE SIGNAL ;
    PORT
      LAYER M5 ;
        RECT  210.816 224.556 210.84 224.64 ;
    END
  END i_lim[21]
  PIN i_lim[22]
    DIRECTION INPUT ;
    USE SIGNAL ;
    PORT
      LAYER M5 ;
        RECT  211.488 224.556 211.512 224.64 ;
    END
  END i_lim[22]
  PIN i_lim[23]
    DIRECTION INPUT ;
    USE SIGNAL ;
    PORT
      LAYER M5 ;
        RECT  212.208 224.556 212.232 224.64 ;
    END
  END i_lim[23]
  PIN i_lim[24]
    DIRECTION INPUT ;
    USE SIGNAL ;
    PORT
      LAYER M5 ;
        RECT  212.88 224.556 212.904 224.64 ;
    END
  END i_lim[24]
  PIN i_lim[25]
    DIRECTION INPUT ;
    USE SIGNAL ;
    PORT
      LAYER M5 ;
        RECT  213.6 224.556 213.624 224.64 ;
    END
  END i_lim[25]
  PIN i_lim[26]
    DIRECTION INPUT ;
    USE SIGNAL ;
    PORT
      LAYER M5 ;
        RECT  214.32 224.556 214.344 224.64 ;
    END
  END i_lim[26]
  PIN i_lim[27]
    DIRECTION INPUT ;
    USE SIGNAL ;
    PORT
      LAYER M5 ;
        RECT  214.992 224.556 215.016 224.64 ;
    END
  END i_lim[27]
  PIN i_lim[28]
    DIRECTION INPUT ;
    USE SIGNAL ;
    PORT
      LAYER M5 ;
        RECT  215.712 224.556 215.736 224.64 ;
    END
  END i_lim[28]
  PIN i_lim[29]
    DIRECTION INPUT ;
    USE SIGNAL ;
    PORT
      LAYER M5 ;
        RECT  216.384 224.556 216.408 224.64 ;
    END
  END i_lim[29]
  PIN i_lim[2]
    DIRECTION INPUT ;
    USE SIGNAL ;
    PORT
      LAYER M5 ;
        RECT  197.472 224.556 197.496 224.64 ;
    END
  END i_lim[2]
  PIN i_lim[30]
    DIRECTION INPUT ;
    USE SIGNAL ;
    PORT
      LAYER M5 ;
        RECT  217.104 224.556 217.128 224.64 ;
    END
  END i_lim[30]
  PIN i_lim[31]
    DIRECTION INPUT ;
    USE SIGNAL ;
    PORT
      LAYER M5 ;
        RECT  217.776 224.556 217.8 224.64 ;
    END
  END i_lim[31]
  PIN i_lim[3]
    DIRECTION INPUT ;
    USE SIGNAL ;
    PORT
      LAYER M5 ;
        RECT  198.192 224.556 198.216 224.64 ;
    END
  END i_lim[3]
  PIN i_lim[4]
    DIRECTION INPUT ;
    USE SIGNAL ;
    PORT
      LAYER M5 ;
        RECT  198.912 224.556 198.936 224.64 ;
    END
  END i_lim[4]
  PIN i_lim[5]
    DIRECTION INPUT ;
    USE SIGNAL ;
    PORT
      LAYER M5 ;
        RECT  199.584 224.556 199.608 224.64 ;
    END
  END i_lim[5]
  PIN i_lim[6]
    DIRECTION INPUT ;
    USE SIGNAL ;
    PORT
      LAYER M5 ;
        RECT  200.304 224.556 200.328 224.64 ;
    END
  END i_lim[6]
  PIN i_lim[7]
    DIRECTION INPUT ;
    USE SIGNAL ;
    PORT
      LAYER M5 ;
        RECT  200.976 224.556 201 224.64 ;
    END
  END i_lim[7]
  PIN i_lim[8]
    DIRECTION INPUT ;
    USE SIGNAL ;
    PORT
      LAYER M5 ;
        RECT  201.696 224.556 201.72 224.64 ;
    END
  END i_lim[8]
  PIN i_lim[9]
    DIRECTION INPUT ;
    USE SIGNAL ;
    PORT
      LAYER M5 ;
        RECT  202.416 224.556 202.44 224.64 ;
    END
  END i_lim[9]
  PIN i_v
    DIRECTION INPUT ;
    USE SIGNAL ;
    PORT
      LAYER M5 ;
        RECT  7.872 224.556 7.896 224.64 ;
    END
  END i_v
  PIN i_w[0]
    DIRECTION INPUT ;
    USE SIGNAL ;
    PORT
      LAYER M5 ;
        RECT  173.712 224.556 173.736 224.64 ;
    END
  END i_w[0]
  PIN i_w[10]
    DIRECTION INPUT ;
    USE SIGNAL ;
    PORT
      LAYER M5 ;
        RECT  180.672 224.556 180.696 224.64 ;
    END
  END i_w[10]
  PIN i_w[11]
    DIRECTION INPUT ;
    USE SIGNAL ;
    PORT
      LAYER M5 ;
        RECT  181.392 224.556 181.416 224.64 ;
    END
  END i_w[11]
  PIN i_w[12]
    DIRECTION INPUT ;
    USE SIGNAL ;
    PORT
      LAYER M5 ;
        RECT  182.064 224.556 182.088 224.64 ;
    END
  END i_w[12]
  PIN i_w[13]
    DIRECTION INPUT ;
    USE SIGNAL ;
    PORT
      LAYER M5 ;
        RECT  182.784 224.556 182.808 224.64 ;
    END
  END i_w[13]
  PIN i_w[14]
    DIRECTION INPUT ;
    USE SIGNAL ;
    PORT
      LAYER M5 ;
        RECT  183.504 224.556 183.528 224.64 ;
    END
  END i_w[14]
  PIN i_w[15]
    DIRECTION INPUT ;
    USE SIGNAL ;
    PORT
      LAYER M5 ;
        RECT  184.176 224.556 184.2 224.64 ;
    END
  END i_w[15]
  PIN i_w[16]
    DIRECTION INPUT ;
    USE SIGNAL ;
    PORT
      LAYER M5 ;
        RECT  184.896 224.556 184.92 224.64 ;
    END
  END i_w[16]
  PIN i_w[17]
    DIRECTION INPUT ;
    USE SIGNAL ;
    PORT
      LAYER M5 ;
        RECT  185.616 224.556 185.64 224.64 ;
    END
  END i_w[17]
  PIN i_w[18]
    DIRECTION INPUT ;
    USE SIGNAL ;
    PORT
      LAYER M5 ;
        RECT  186.288 224.556 186.312 224.64 ;
    END
  END i_w[18]
  PIN i_w[19]
    DIRECTION INPUT ;
    USE SIGNAL ;
    PORT
      LAYER M5 ;
        RECT  187.008 224.556 187.032 224.64 ;
    END
  END i_w[19]
  PIN i_w[1]
    DIRECTION INPUT ;
    USE SIGNAL ;
    PORT
      LAYER M5 ;
        RECT  174.384 224.556 174.408 224.64 ;
    END
  END i_w[1]
  PIN i_w[20]
    DIRECTION INPUT ;
    USE SIGNAL ;
    PORT
      LAYER M5 ;
        RECT  187.68 224.556 187.704 224.64 ;
    END
  END i_w[20]
  PIN i_w[21]
    DIRECTION INPUT ;
    USE SIGNAL ;
    PORT
      LAYER M5 ;
        RECT  188.4 224.556 188.424 224.64 ;
    END
  END i_w[21]
  PIN i_w[22]
    DIRECTION INPUT ;
    USE SIGNAL ;
    PORT
      LAYER M5 ;
        RECT  189.12 224.556 189.144 224.64 ;
    END
  END i_w[22]
  PIN i_w[23]
    DIRECTION INPUT ;
    USE SIGNAL ;
    PORT
      LAYER M5 ;
        RECT  189.792 224.556 189.816 224.64 ;
    END
  END i_w[23]
  PIN i_w[24]
    DIRECTION INPUT ;
    USE SIGNAL ;
    PORT
      LAYER M5 ;
        RECT  190.512 224.556 190.536 224.64 ;
    END
  END i_w[24]
  PIN i_w[25]
    DIRECTION INPUT ;
    USE SIGNAL ;
    PORT
      LAYER M5 ;
        RECT  191.184 224.556 191.208 224.64 ;
    END
  END i_w[25]
  PIN i_w[26]
    DIRECTION INPUT ;
    USE SIGNAL ;
    PORT
      LAYER M5 ;
        RECT  191.904 224.556 191.928 224.64 ;
    END
  END i_w[26]
  PIN i_w[27]
    DIRECTION INPUT ;
    USE SIGNAL ;
    PORT
      LAYER M5 ;
        RECT  192.576 224.556 192.6 224.64 ;
    END
  END i_w[27]
  PIN i_w[28]
    DIRECTION INPUT ;
    USE SIGNAL ;
    PORT
      LAYER M5 ;
        RECT  193.296 224.556 193.32 224.64 ;
    END
  END i_w[28]
  PIN i_w[29]
    DIRECTION INPUT ;
    USE SIGNAL ;
    PORT
      LAYER M5 ;
        RECT  194.016 224.556 194.04 224.64 ;
    END
  END i_w[29]
  PIN i_w[2]
    DIRECTION INPUT ;
    USE SIGNAL ;
    PORT
      LAYER M5 ;
        RECT  175.104 224.556 175.128 224.64 ;
    END
  END i_w[2]
  PIN i_w[30]
    DIRECTION INPUT ;
    USE SIGNAL ;
    PORT
      LAYER M5 ;
        RECT  194.688 224.556 194.712 224.64 ;
    END
  END i_w[30]
  PIN i_w[31]
    DIRECTION INPUT ;
    USE SIGNAL ;
    PORT
      LAYER M5 ;
        RECT  195.408 224.556 195.432 224.64 ;
    END
  END i_w[31]
  PIN i_w[3]
    DIRECTION INPUT ;
    USE SIGNAL ;
    PORT
      LAYER M5 ;
        RECT  175.776 224.556 175.8 224.64 ;
    END
  END i_w[3]
  PIN i_w[4]
    DIRECTION INPUT ;
    USE SIGNAL ;
    PORT
      LAYER M5 ;
        RECT  176.496 224.556 176.52 224.64 ;
    END
  END i_w[4]
  PIN i_w[5]
    DIRECTION INPUT ;
    USE SIGNAL ;
    PORT
      LAYER M5 ;
        RECT  177.216 224.556 177.24 224.64 ;
    END
  END i_w[5]
  PIN i_w[6]
    DIRECTION INPUT ;
    USE SIGNAL ;
    PORT
      LAYER M5 ;
        RECT  177.888 224.556 177.912 224.64 ;
    END
  END i_w[6]
  PIN i_w[7]
    DIRECTION INPUT ;
    USE SIGNAL ;
    PORT
      LAYER M5 ;
        RECT  178.608 224.556 178.632 224.64 ;
    END
  END i_w[7]
  PIN i_w[8]
    DIRECTION INPUT ;
    USE SIGNAL ;
    PORT
      LAYER M5 ;
        RECT  179.328 224.556 179.352 224.64 ;
    END
  END i_w[8]
  PIN i_w[9]
    DIRECTION INPUT ;
    USE SIGNAL ;
    PORT
      LAYER M5 ;
        RECT  180 224.556 180.024 224.64 ;
    END
  END i_w[9]
  PIN o_d[0]
    DIRECTION OUTPUT ;
    USE SIGNAL ;
    PORT
      LAYER M5 ;
        RECT  13.44 0 13.464 0.084 ;
    END
  END o_d[0]
  PIN o_d[10]
    DIRECTION OUTPUT ;
    USE SIGNAL ;
    PORT
      LAYER M5 ;
        RECT  44.736 0 44.76 0.084 ;
    END
  END o_d[10]
  PIN o_d[11]
    DIRECTION OUTPUT ;
    USE SIGNAL ;
    PORT
      LAYER M5 ;
        RECT  47.904 0 47.928 0.084 ;
    END
  END o_d[11]
  PIN o_d[12]
    DIRECTION OUTPUT ;
    USE SIGNAL ;
    PORT
      LAYER M5 ;
        RECT  50.976 0 51 0.084 ;
    END
  END o_d[12]
  PIN o_d[13]
    DIRECTION OUTPUT ;
    USE SIGNAL ;
    PORT
      LAYER M5 ;
        RECT  54.144 0 54.168 0.084 ;
    END
  END o_d[13]
  PIN o_d[14]
    DIRECTION OUTPUT ;
    USE SIGNAL ;
    PORT
      LAYER M5 ;
        RECT  57.312 0 57.336 0.084 ;
    END
  END o_d[14]
  PIN o_d[15]
    DIRECTION OUTPUT ;
    USE SIGNAL ;
    PORT
      LAYER M5 ;
        RECT  60.432 0 60.456 0.084 ;
    END
  END o_d[15]
  PIN o_d[16]
    DIRECTION OUTPUT ;
    USE SIGNAL ;
    PORT
      LAYER M5 ;
        RECT  63.6 0 63.624 0.084 ;
    END
  END o_d[16]
  PIN o_d[17]
    DIRECTION OUTPUT ;
    USE SIGNAL ;
    PORT
      LAYER M5 ;
        RECT  66.72 0 66.744 0.084 ;
    END
  END o_d[17]
  PIN o_d[18]
    DIRECTION OUTPUT ;
    USE SIGNAL ;
    PORT
      LAYER M5 ;
        RECT  69.888 0 69.912 0.084 ;
    END
  END o_d[18]
  PIN o_d[19]
    DIRECTION OUTPUT ;
    USE SIGNAL ;
    PORT
      LAYER M5 ;
        RECT  73.008 0 73.032 0.084 ;
    END
  END o_d[19]
  PIN o_d[1]
    DIRECTION OUTPUT ;
    USE SIGNAL ;
    PORT
      LAYER M5 ;
        RECT  16.464 0 16.488 0.084 ;
    END
  END o_d[1]
  PIN o_d[20]
    DIRECTION OUTPUT ;
    USE SIGNAL ;
    PORT
      LAYER M5 ;
        RECT  76.176 0 76.2 0.084 ;
    END
  END o_d[20]
  PIN o_d[21]
    DIRECTION OUTPUT ;
    USE SIGNAL ;
    PORT
      LAYER M5 ;
        RECT  79.296 0 79.32 0.084 ;
    END
  END o_d[21]
  PIN o_d[22]
    DIRECTION OUTPUT ;
    USE SIGNAL ;
    PORT
      LAYER M5 ;
        RECT  82.416 0 82.44 0.084 ;
    END
  END o_d[22]
  PIN o_d[23]
    DIRECTION OUTPUT ;
    USE SIGNAL ;
    PORT
      LAYER M5 ;
        RECT  85.584 0 85.608 0.084 ;
    END
  END o_d[23]
  PIN o_d[24]
    DIRECTION OUTPUT ;
    USE SIGNAL ;
    PORT
      LAYER M5 ;
        RECT  88.752 0 88.776 0.084 ;
    END
  END o_d[24]
  PIN o_d[25]
    DIRECTION OUTPUT ;
    USE SIGNAL ;
    PORT
      LAYER M5 ;
        RECT  91.872 0 91.896 0.084 ;
    END
  END o_d[25]
  PIN o_d[26]
    DIRECTION OUTPUT ;
    USE SIGNAL ;
    PORT
      LAYER M5 ;
        RECT  95.04 0 95.064 0.084 ;
    END
  END o_d[26]
  PIN o_d[27]
    DIRECTION OUTPUT ;
    USE SIGNAL ;
    PORT
      LAYER M5 ;
        RECT  98.16 0 98.184 0.084 ;
    END
  END o_d[27]
  PIN o_d[28]
    DIRECTION OUTPUT ;
    USE SIGNAL ;
    PORT
      LAYER M5 ;
        RECT  101.28 0 101.304 0.084 ;
    END
  END o_d[28]
  PIN o_d[29]
    DIRECTION OUTPUT ;
    USE SIGNAL ;
    PORT
      LAYER M5 ;
        RECT  104.448 0 104.472 0.084 ;
    END
  END o_d[29]
  PIN o_d[2]
    DIRECTION OUTPUT ;
    USE SIGNAL ;
    PORT
      LAYER M5 ;
        RECT  19.584 0 19.608 0.084 ;
    END
  END o_d[2]
  PIN o_d[30]
    DIRECTION OUTPUT ;
    USE SIGNAL ;
    PORT
      LAYER M5 ;
        RECT  107.616 0 107.64 0.084 ;
    END
  END o_d[30]
  PIN o_d[31]
    DIRECTION OUTPUT ;
    USE SIGNAL ;
    PORT
      LAYER M5 ;
        RECT  110.736 0 110.76 0.084 ;
    END
  END o_d[31]
  PIN o_d[32]
    DIRECTION OUTPUT ;
    USE SIGNAL ;
    PORT
      LAYER M5 ;
        RECT  113.856 0 113.88 0.084 ;
    END
  END o_d[32]
  PIN o_d[33]
    DIRECTION OUTPUT ;
    USE SIGNAL ;
    PORT
      LAYER M5 ;
        RECT  117.024 0 117.048 0.084 ;
    END
  END o_d[33]
  PIN o_d[34]
    DIRECTION OUTPUT ;
    USE SIGNAL ;
    PORT
      LAYER M5 ;
        RECT  120.144 0 120.168 0.084 ;
    END
  END o_d[34]
  PIN o_d[35]
    DIRECTION OUTPUT ;
    USE SIGNAL ;
    PORT
      LAYER M5 ;
        RECT  123.312 0 123.336 0.084 ;
    END
  END o_d[35]
  PIN o_d[36]
    DIRECTION OUTPUT ;
    USE SIGNAL ;
    PORT
      LAYER M5 ;
        RECT  126.48 0 126.504 0.084 ;
    END
  END o_d[36]
  PIN o_d[37]
    DIRECTION OUTPUT ;
    USE SIGNAL ;
    PORT
      LAYER M5 ;
        RECT  129.6 0 129.624 0.084 ;
    END
  END o_d[37]
  PIN o_d[38]
    DIRECTION OUTPUT ;
    USE SIGNAL ;
    PORT
      LAYER M5 ;
        RECT  132.72 0 132.744 0.084 ;
    END
  END o_d[38]
  PIN o_d[39]
    DIRECTION OUTPUT ;
    USE SIGNAL ;
    PORT
      LAYER M5 ;
        RECT  135.888 0 135.912 0.084 ;
    END
  END o_d[39]
  PIN o_d[3]
    DIRECTION OUTPUT ;
    USE SIGNAL ;
    PORT
      LAYER M5 ;
        RECT  22.752 0 22.776 0.084 ;
    END
  END o_d[3]
  PIN o_d[40]
    DIRECTION OUTPUT ;
    USE SIGNAL ;
    PORT
      LAYER M5 ;
        RECT  139.008 0 139.032 0.084 ;
    END
  END o_d[40]
  PIN o_d[41]
    DIRECTION OUTPUT ;
    USE SIGNAL ;
    PORT
      LAYER M5 ;
        RECT  142.176 0 142.2 0.084 ;
    END
  END o_d[41]
  PIN o_d[42]
    DIRECTION OUTPUT ;
    USE SIGNAL ;
    PORT
      LAYER M5 ;
        RECT  145.296 0 145.32 0.084 ;
    END
  END o_d[42]
  PIN o_d[43]
    DIRECTION OUTPUT ;
    USE SIGNAL ;
    PORT
      LAYER M5 ;
        RECT  148.464 0 148.488 0.084 ;
    END
  END o_d[43]
  PIN o_d[44]
    DIRECTION OUTPUT ;
    USE SIGNAL ;
    PORT
      LAYER M5 ;
        RECT  151.584 0 151.608 0.084 ;
    END
  END o_d[44]
  PIN o_d[45]
    DIRECTION OUTPUT ;
    USE SIGNAL ;
    PORT
      LAYER M5 ;
        RECT  154.752 0 154.776 0.084 ;
    END
  END o_d[45]
  PIN o_d[46]
    DIRECTION OUTPUT ;
    USE SIGNAL ;
    PORT
      LAYER M5 ;
        RECT  157.872 0 157.896 0.084 ;
    END
  END o_d[46]
  PIN o_d[47]
    DIRECTION OUTPUT ;
    USE SIGNAL ;
    PORT
      LAYER M5 ;
        RECT  161.04 0 161.064 0.084 ;
    END
  END o_d[47]
  PIN o_d[48]
    DIRECTION OUTPUT ;
    USE SIGNAL ;
    PORT
      LAYER M5 ;
        RECT  164.16 0 164.184 0.084 ;
    END
  END o_d[48]
  PIN o_d[49]
    DIRECTION OUTPUT ;
    USE SIGNAL ;
    PORT
      LAYER M5 ;
        RECT  167.328 0 167.352 0.084 ;
    END
  END o_d[49]
  PIN o_d[4]
    DIRECTION OUTPUT ;
    USE SIGNAL ;
    PORT
      LAYER M5 ;
        RECT  25.872 0 25.896 0.084 ;
    END
  END o_d[4]
  PIN o_d[50]
    DIRECTION OUTPUT ;
    USE SIGNAL ;
    PORT
      LAYER M5 ;
        RECT  170.448 0 170.472 0.084 ;
    END
  END o_d[50]
  PIN o_d[51]
    DIRECTION OUTPUT ;
    USE SIGNAL ;
    PORT
      LAYER M5 ;
        RECT  173.616 0 173.64 0.084 ;
    END
  END o_d[51]
  PIN o_d[52]
    DIRECTION OUTPUT ;
    USE SIGNAL ;
    PORT
      LAYER M5 ;
        RECT  176.736 0 176.76 0.084 ;
    END
  END o_d[52]
  PIN o_d[53]
    DIRECTION OUTPUT ;
    USE SIGNAL ;
    PORT
      LAYER M5 ;
        RECT  179.856 0 179.88 0.084 ;
    END
  END o_d[53]
  PIN o_d[54]
    DIRECTION OUTPUT ;
    USE SIGNAL ;
    PORT
      LAYER M5 ;
        RECT  183.024 0 183.048 0.084 ;
    END
  END o_d[54]
  PIN o_d[55]
    DIRECTION OUTPUT ;
    USE SIGNAL ;
    PORT
      LAYER M5 ;
        RECT  186.144 0 186.168 0.084 ;
    END
  END o_d[55]
  PIN o_d[56]
    DIRECTION OUTPUT ;
    USE SIGNAL ;
    PORT
      LAYER M5 ;
        RECT  189.312 0 189.336 0.084 ;
    END
  END o_d[56]
  PIN o_d[57]
    DIRECTION OUTPUT ;
    USE SIGNAL ;
    PORT
      LAYER M5 ;
        RECT  192.432 0 192.456 0.084 ;
    END
  END o_d[57]
  PIN o_d[58]
    DIRECTION OUTPUT ;
    USE SIGNAL ;
    PORT
      LAYER M5 ;
        RECT  195.6 0 195.624 0.084 ;
    END
  END o_d[58]
  PIN o_d[59]
    DIRECTION OUTPUT ;
    USE SIGNAL ;
    PORT
      LAYER M5 ;
        RECT  198.72 0 198.744 0.084 ;
    END
  END o_d[59]
  PIN o_d[5]
    DIRECTION OUTPUT ;
    USE SIGNAL ;
    PORT
      LAYER M5 ;
        RECT  29.04 0 29.064 0.084 ;
    END
  END o_d[5]
  PIN o_d[60]
    DIRECTION OUTPUT ;
    USE SIGNAL ;
    PORT
      LAYER M5 ;
        RECT  201.888 0 201.912 0.084 ;
    END
  END o_d[60]
  PIN o_d[61]
    DIRECTION OUTPUT ;
    USE SIGNAL ;
    PORT
      LAYER M5 ;
        RECT  205.008 0 205.032 0.084 ;
    END
  END o_d[61]
  PIN o_d[62]
    DIRECTION OUTPUT ;
    USE SIGNAL ;
    PORT
      LAYER M5 ;
        RECT  208.128 0 208.152 0.084 ;
    END
  END o_d[62]
  PIN o_d[63]
    DIRECTION OUTPUT ;
    USE SIGNAL ;
    PORT
      LAYER M5 ;
        RECT  211.296 0 211.32 0.084 ;
    END
  END o_d[63]
  PIN o_d[6]
    DIRECTION OUTPUT ;
    USE SIGNAL ;
    PORT
      LAYER M5 ;
        RECT  32.16 0 32.184 0.084 ;
    END
  END o_d[6]
  PIN o_d[7]
    DIRECTION OUTPUT ;
    USE SIGNAL ;
    PORT
      LAYER M5 ;
        RECT  35.328 0 35.352 0.084 ;
    END
  END o_d[7]
  PIN o_d[8]
    DIRECTION OUTPUT ;
    USE SIGNAL ;
    PORT
      LAYER M5 ;
        RECT  38.448 0 38.472 0.084 ;
    END
  END o_d[8]
  PIN o_d[9]
    DIRECTION OUTPUT ;
    USE SIGNAL ;
    PORT
      LAYER M5 ;
        RECT  41.616 0 41.64 0.084 ;
    END
  END o_d[9]
  PIN o_f
    DIRECTION OUTPUT ;
    USE SIGNAL ;
    PORT
      LAYER M5 ;
        RECT  215.52 0 215.544 0.084 ;
    END
  END o_f
  PIN o_v
    DIRECTION OUTPUT ;
    USE SIGNAL ;
    PORT
      LAYER M5 ;
        RECT  9.12 0 9.144 0.084 ;
    END
  END o_v
  PIN rst_n
    DIRECTION INPUT ;
    USE SIGNAL ;
    PORT
      LAYER M5 ;
        RECT  167.952 0 167.976 0.084 ;
    END
  END rst_n
  PIN VDD
    DIRECTION INOUT ;
    USE POWER ;
    PORT
      LAYER M5 ;
        RECT  218.196 4.311 218.316 220.329 ;
        RECT  213.876 4.311 213.996 220.329 ;
        RECT  209.556 4.311 209.676 220.329 ;
        RECT  205.236 4.311 205.356 220.329 ;
        RECT  200.916 4.311 201.036 220.329 ;
        RECT  196.596 4.311 196.716 220.329 ;
        RECT  192.276 4.311 192.396 220.329 ;
        RECT  187.956 4.311 188.076 220.329 ;
        RECT  183.636 4.311 183.756 220.329 ;
        RECT  179.316 4.311 179.436 220.329 ;
        RECT  174.996 4.311 175.116 220.329 ;
        RECT  170.676 4.311 170.796 220.329 ;
        RECT  166.356 4.311 166.476 220.329 ;
        RECT  162.036 4.311 162.156 220.329 ;
        RECT  157.716 4.311 157.836 220.329 ;
        RECT  153.396 4.311 153.516 220.329 ;
        RECT  149.076 4.311 149.196 220.329 ;
        RECT  144.756 4.311 144.876 220.329 ;
        RECT  140.436 4.311 140.556 220.329 ;
        RECT  136.116 4.311 136.236 220.329 ;
        RECT  131.796 4.311 131.916 220.329 ;
        RECT  127.476 4.311 127.596 220.329 ;
        RECT  123.156 4.311 123.276 220.329 ;
        RECT  118.836 4.311 118.956 220.329 ;
        RECT  114.516 4.311 114.636 220.329 ;
        RECT  110.196 4.311 110.316 220.329 ;
        RECT  105.876 4.311 105.996 220.329 ;
        RECT  101.556 4.311 101.676 220.329 ;
        RECT  97.236 4.311 97.356 220.329 ;
        RECT  92.916 4.311 93.036 220.329 ;
        RECT  88.596 4.311 88.716 220.329 ;
        RECT  84.276 4.311 84.396 220.329 ;
        RECT  79.956 4.311 80.076 220.329 ;
        RECT  75.636 4.311 75.756 220.329 ;
        RECT  71.316 4.311 71.436 220.329 ;
        RECT  66.996 4.311 67.116 220.329 ;
        RECT  62.676 4.311 62.796 220.329 ;
        RECT  58.356 4.311 58.476 220.329 ;
        RECT  54.036 4.311 54.156 220.329 ;
        RECT  49.716 4.311 49.836 220.329 ;
        RECT  45.396 4.311 45.516 220.329 ;
        RECT  41.076 4.311 41.196 220.329 ;
        RECT  36.756 4.311 36.876 220.329 ;
        RECT  32.436 4.311 32.556 220.329 ;
        RECT  28.116 4.311 28.236 220.329 ;
        RECT  23.796 4.311 23.916 220.329 ;
        RECT  19.476 4.311 19.596 220.329 ;
        RECT  15.156 4.311 15.276 220.329 ;
        RECT  10.836 4.311 10.956 220.329 ;
        RECT  6.516 4.311 6.636 220.329 ;
    END
  END VDD
  PIN VSS
    DIRECTION INOUT ;
    USE GROUND ;
    PORT
      LAYER M5 ;
        RECT  218.004 4.297 218.124 220.343 ;
        RECT  213.684 4.297 213.804 220.343 ;
        RECT  209.364 4.297 209.484 220.343 ;
        RECT  205.044 4.297 205.164 220.343 ;
        RECT  200.724 4.297 200.844 220.343 ;
        RECT  196.404 4.297 196.524 220.343 ;
        RECT  192.084 4.297 192.204 220.343 ;
        RECT  187.764 4.297 187.884 220.343 ;
        RECT  183.444 4.297 183.564 220.343 ;
        RECT  179.124 4.297 179.244 220.343 ;
        RECT  174.804 4.297 174.924 220.343 ;
        RECT  170.484 4.297 170.604 220.343 ;
        RECT  166.164 4.297 166.284 220.343 ;
        RECT  161.844 4.297 161.964 220.343 ;
        RECT  157.524 4.297 157.644 220.343 ;
        RECT  153.204 4.297 153.324 220.343 ;
        RECT  148.884 4.297 149.004 220.343 ;
        RECT  144.564 4.297 144.684 220.343 ;
        RECT  140.244 4.297 140.364 220.343 ;
        RECT  135.924 4.297 136.044 220.343 ;
        RECT  131.604 4.297 131.724 220.343 ;
        RECT  127.284 4.297 127.404 220.343 ;
        RECT  122.964 4.297 123.084 220.343 ;
        RECT  118.644 4.297 118.764 220.343 ;
        RECT  114.324 4.297 114.444 220.343 ;
        RECT  110.004 4.297 110.124 220.343 ;
        RECT  105.684 4.297 105.804 220.343 ;
        RECT  101.364 4.297 101.484 220.343 ;
        RECT  97.044 4.297 97.164 220.343 ;
        RECT  92.724 4.297 92.844 220.343 ;
        RECT  88.404 4.297 88.524 220.343 ;
        RECT  84.084 4.297 84.204 220.343 ;
        RECT  79.764 4.297 79.884 220.343 ;
        RECT  75.444 4.297 75.564 220.343 ;
        RECT  71.124 4.297 71.244 220.343 ;
        RECT  66.804 4.297 66.924 220.343 ;
        RECT  62.484 4.297 62.604 220.343 ;
        RECT  58.164 4.297 58.284 220.343 ;
        RECT  53.844 4.297 53.964 220.343 ;
        RECT  49.524 4.297 49.644 220.343 ;
        RECT  45.204 4.297 45.324 220.343 ;
        RECT  40.884 4.297 41.004 220.343 ;
        RECT  36.564 4.297 36.684 220.343 ;
        RECT  32.244 4.297 32.364 220.343 ;
        RECT  27.924 4.297 28.044 220.343 ;
        RECT  23.604 4.297 23.724 220.343 ;
        RECT  19.284 4.297 19.404 220.343 ;
        RECT  14.964 4.297 15.084 220.343 ;
        RECT  10.644 4.297 10.764 220.343 ;
        RECT  6.324 4.297 6.444 220.343 ;
    END
  END VSS
  OBS
    LAYER RVTN ;
     RECT  4.32 0 220.32 224.64 ;
    LAYER RVTP ;
     RECT  4.32 0 220.32 224.64 ;
    LAYER M1 ;
     RECT  4.32 0 220.32 224.64 ;
    LAYER M2 ;
     RECT  4.32 0 220.32 224.64 ;
    LAYER M3 ;
     RECT  4.32 0 220.32 224.64 ;
    LAYER M4 ;
     RECT  4.32 0 220.32 224.64 ;
    LAYER M5 ;
     RECT  4.32 0 220.32 224.64 ;
  END
END ot_s81sl_vsw
END LIBRARY
